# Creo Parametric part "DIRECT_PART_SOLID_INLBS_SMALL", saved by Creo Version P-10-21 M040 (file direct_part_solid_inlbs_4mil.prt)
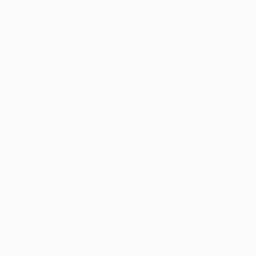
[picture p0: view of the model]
Units: Inch lbm Second (Pro/E Default); INCH, POUND, SECS

Created from: INLBS_PART_SOLID.PRT

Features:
  1. datum plane "RIGHT"
  2. datum plane "TOP"
  3. datum plane "FRONT"
  4. coordinate system

Surfaces: 3 plane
